! (c) 2009  Infineon Technologies AG, Munich
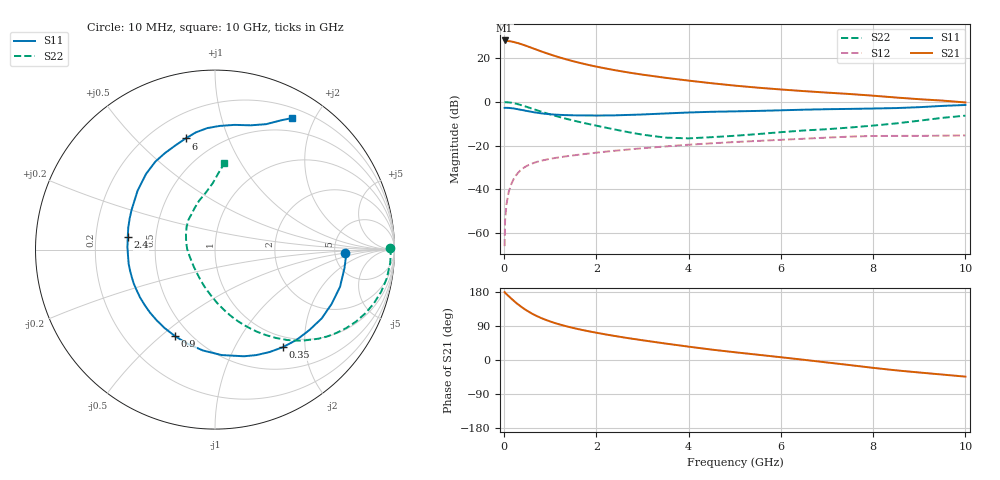
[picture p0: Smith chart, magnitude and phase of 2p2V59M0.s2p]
! Infineon Technologies  Discrete & RF Semiconductors
! BFP420
! VCE =  2.5 V,  IC =  9.0 mA
! Common Emitter S-Parameters:  Nov 2009
# GHz  S  MA  R  50
!  f  S11  S21  S12  S22
! GHz  MAG  ANG  MAG  ANG  MAG  ANG  MAG  ANG
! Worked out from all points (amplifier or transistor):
!   46 points, 10 MHz to 10 GHz, reference 50 ohm
!   highest |S21| = 28.1 dB at 10 MHz (marker M1)
!   |S21| within 3 dB of that: start of sweep to 546.8 MHz
!   unconditionally stable (mu >= 1): 2.446 GHz to end of sweep
!   at 300 MHz: K = 0.17, MSG = 29.7 dB, |S12| = -32.5 dB
!   at 1.7 GHz: K = 0.79, MSG = 20.7 dB, |S12| = -24.0 dB
!   at 10 GHz: K = 1.09, MAG = 5.7 dB, |S12| = -15.4 dB
!   S11 on the Smith chart (normalised r, x): 10 MHz: 6.27, -0.57; 350 MHz: 0.82, -1.59; 900 MHz: 0.42, -0.56; 2.4 GHz: 0.34, +0.06; 6 GHz: 0.34, +0.71; 10 GHz: 0.33, +1.69
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0.01  0.727 -1.7  25.34 179.1  0.0005 87.4  0.9741 0.6
0.02  0.7302 -3.6  24.69 177.6  0.0019 84.8  0.9795 -1.7
0.05  0.7287 -8.2  24.64 173.9  0.0045 85.6  0.9788 -4.6
0.1  0.7268 -16.6  24.49 168.3  0.0088 82.4  0.9703 -9.5
0.2  0.7075 -32.8  23.47 157.2  0.0167 74.7  0.9346 -18.7
0.25  0.6909 -40.5  22.72 151.8  0.0204 71.4  0.9103 -22.9
0.35  0.6621 -55.2  21.21 142.3  0.0269 65.2  0.8527 -30.8
0.45  0.6312 -68.6  19.54 133.7  0.0323 60.1  0.7911 -37.7
0.6  0.5888 -86.4  17.11 122.6  0.0386 54.1  0.7012 -46.4
0.7  0.5659 -96.9  15.64 116.4  0.042 51.1  0.6469 -51.2
0.9  0.5313 -114.7  13.14 106.0  0.0474 46.7  0.5547 -59.2
1.2  0.5042 -136.1  10.38 93.9  0.0539 42.9  0.4494 -69.1
1.4  0.4954 -147.5  9.031 87.4  0.0578 41.3  0.3965 -74.7
1.7  0.4883 -162.0  7.515 79.1  0.0633 39.4  0.3336 -82.3
2.4  0.491 172.0  5.303 63.4  0.0761 35.8  0.2329 -100.5
3.5  0.5421 142.7  3.545 43.4  0.0956 29.4  0.1518 -141.2
4.5  0.5923 124.1  2.664 27.4  0.1126 22.4  0.1556 178.1
5.5  0.6202 111.1  2.109 13.9  0.1277 15.5  0.1831 152.1
6  0.6404 104.8  1.917 7.3  0.1352 12.0  0.2024 141.5
7  0.6784 93.6  1.626 -6.5  0.152 3.9  0.2367 123.6
8.5  0.7203 74.0  1.254 -27.3  0.1664 -11.6  0.3212 99.2
10  0.8475 59.8  0.968 -43.9  0.1706 -21.9  0.483 83.8
